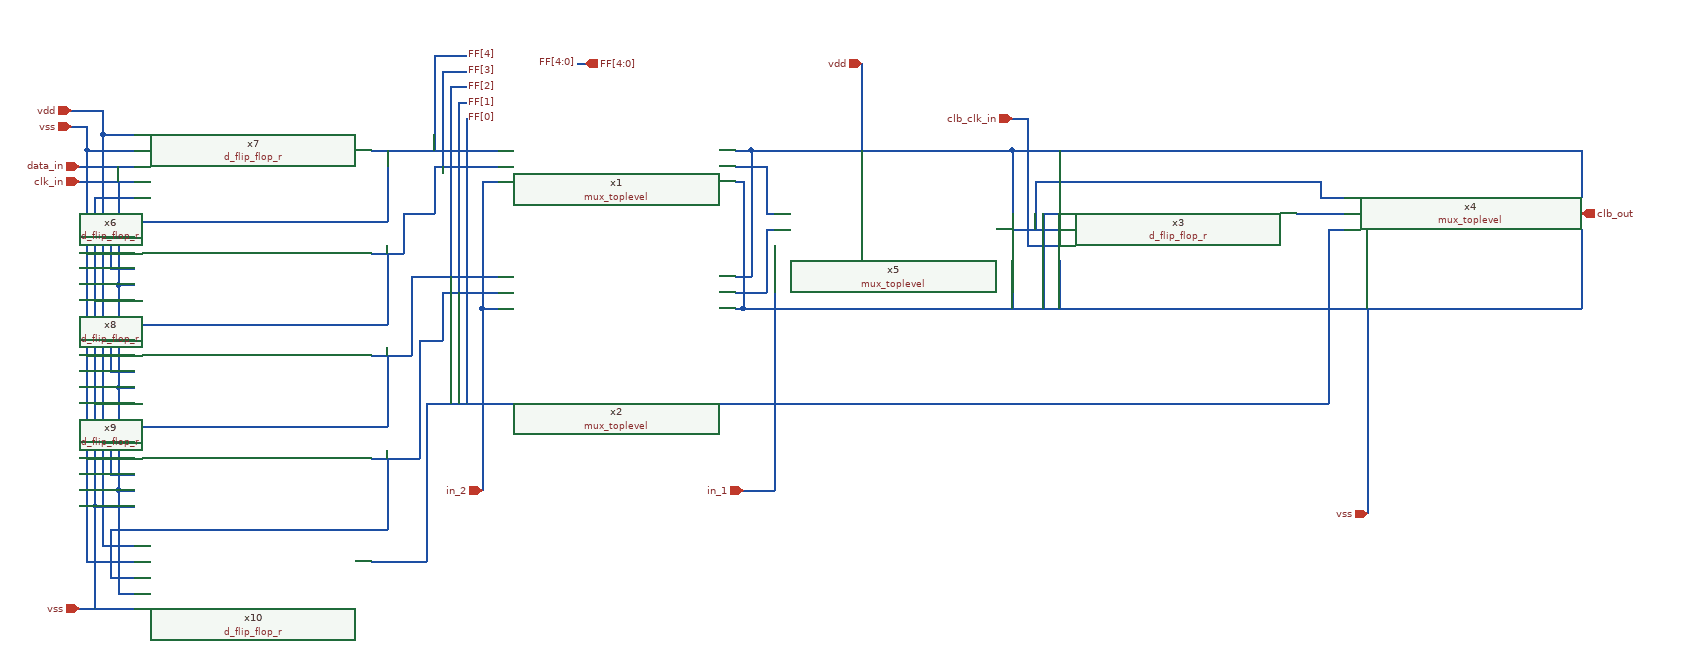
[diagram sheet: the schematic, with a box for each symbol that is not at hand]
v {xschem version=3.4.7 file_version=1.2}
G {}
K {}
V {}
S {}
E {}
N 230 -20 270 -20 {lab=#net1}
N 270 -20 270 40 {lab=#net1}
N 270 40 280 40 {lab=#net1}
N 230 140 270 140 {lab=#net2}
N 270 60 270 140 {lab=#net2}
N 270 60 280 60 {lab=#net2}
N 230 0 240 0 {lab=vss}
N 240 -0 240 160 {lab=vss}
N 230 160 240 160 {lab=vss}
N 230 120 250 120 {lab=vdd}
N 250 -40 250 120 {lab=vdd}
N 230 -40 250 -40 {lab=vdd}
N 250 -40 580 -40 {lab=vdd}
N 580 -40 580 40 {lab=vdd}
N 580 -40 1220 -40 {lab=vdd}
N 240 160 1220 160 {lab=vss}
N 580 80 580 160 {lab=vss}
N 580 60 640 60 {lab=#net3}
N 610 -0 610 60 {lab=#net3}
N 610 -0 900 -0 {lab=#net3}
N -90 -0 -90 160 {lab=in_2}
N -90 160 -70 160 {lab=in_2}
N -90 160 -90 270 {lab=in_2}
N 240 390 270 390 {lab=in_1}
N -90 -0 -70 0 {lab=in_2}
N -160 -40 -70 -40 {lab=FF[4]}
N -150 -20 -70 -20 {lab=FF[3]}
N -150 -20 -150 40 {lab=FF[3]}
N -160 40 -150 40 {lab=FF[3]}
N -160 120 -70 120 {lab=FF[2]}
N -160 200 -140 200 {lab=FF[1]}
N -140 140 -140 200 {lab=FF[1]}
N -140 140 -70 140 {lab=FF[1]}
N -90 270 -90 390 {lab=in_2}
N 270 390 280 390 {lab=in_1}
N -160 280 910 280 {lab=FF[0]}
N 910 280 920 280 {lab=FF[0]}
N 580 -80 590 -80 {lab=clb_clk_in}
N 1030 160 1030 420 {lab=vss}
N 390 -150 390 -40 {lab=vdd}
N 280 80 280 390 {lab=in_1}
N -110 -80 -110 280 {lab=FF[0]}
N -120 -100 -110 -100 {lab=FF[1]}
N -130 -120 -110 -120 {lab=FF[2]}
N -130 -120 -130 120 {lab=FF[2]}
N -120 -100 -120 140 {lab=FF[1]}
N -140 -140 -110 -140 {lab=FF[3]}
N -140 -140 -140 -20 {lab=FF[3]}
N -150 -160 -110 -160 {lab=FF[4]}
N -150 -160 -150 -40 {lab=FF[4]}
N 30 -150 40 -150 {lab=FF[4:0]}
N -230 -40 -160 -40 {lab=FF[4]}
N -190 40 -160 40 {lab=FF[3]}
N -190 40 -190 90 {lab=FF[3]}
N -230 90 -190 90 {lab=FF[3]}
N -230 220 -180 220 {lab=FF[2]}
N -180 120 -180 220 {lab=FF[2]}
N -180 120 -160 120 {lab=FF[2]}
N -170 200 -160 200 {lab=FF[1]}
N -170 200 -170 350 {lab=FF[1]}
N -230 350 -170 350 {lab=FF[1]}
N -160 280 -160 480 {lab=FF[0]}
N -230 480 -160 480 {lab=FF[0]}
N -600 -0 -530 -0 {lab=clk_in}
N -550 -0 -550 130 {lab=clk_in}
N -550 130 -530 130 {lab=clk_in}
N -550 130 -550 260 {lab=clk_in}
N -550 260 -530 260 {lab=clk_in}
N -550 260 -550 390 {lab=clk_in}
N -550 390 -530 390 {lab=clk_in}
N -550 390 -550 520 {lab=clk_in}
N -550 520 -530 520 {lab=clk_in}
N -600 -20 -530 -20 {lab=data_in}
N -210 -40 -210 40 {lab=FF[4]}
N -210 40 -210 50 {lab=FF[4]}
N -560 50 -210 50 {lab=FF[4]}
N -560 50 -560 110 {lab=FF[4]}
N -560 110 -530 110 {lab=FF[4]}
N -210 90 -210 180 {lab=FF[3]}
N -560 180 -210 180 {lab=FF[3]}
N -560 180 -560 240 {lab=FF[3]}
N -560 240 -530 240 {lab=FF[3]}
N -210 220 -210 310 {lab=FF[2]}
N -560 310 -210 310 {lab=FF[2]}
N -560 310 -560 370 {lab=FF[2]}
N -560 370 -530 370 {lab=FF[2]}
N -210 350 -210 430 {lab=FF[1]}
N -210 430 -210 440 {lab=FF[1]}
N -560 440 -210 440 {lab=FF[1]}
N -560 440 -560 500 {lab=FF[1]}
N -560 500 -530 500 {lab=FF[1]}
N -600 540 -530 540 {lab=vss}
N -580 410 -530 410 {lab=vss}
N -580 410 -580 540 {lab=vss}
N -580 20 -530 20 {lab=vss}
N -580 20 -580 410 {lab=vss}
N -580 280 -530 280 {lab=vss}
N -580 150 -530 150 {lab=vss}
N -610 -90 -570 -90 {lab=vdd}
N -570 -90 -570 -60 {lab=vdd}
N -570 -60 -530 -60 {lab=vdd}
N -570 -60 -570 460 {lab=vdd}
N -570 460 -530 460 {lab=vdd}
N -570 330 -530 330 {lab=vdd}
N -570 200 -530 200 {lab=vdd}
N -570 70 -530 70 {lab=vdd}
N -590 -40 -530 -40 {lab=vss}
N -590 -70 -590 -40 {lab=vss}
N -610 -70 -590 -70 {lab=vss}
N -590 -40 -590 480 {lab=vss}
N -590 480 -530 480 {lab=vss}
N -590 350 -530 350 {lab=vss}
N -590 220 -530 220 {lab=vss}
N -590 90 -530 90 {lab=vss}
N 940 40 1000 40 {lab=#net4}
N 900 -0 970 -0 {lab=#net3}
N 970 -0 970 20 {lab=#net3}
N 970 20 1000 20 {lab=#net3}
N 980 60 1000 60 {lab=FF[0]}
N 980 60 980 280 {lab=FF[0]}
N 920 280 980 280 {lab=FF[0]}
N 1300 -40 1300 20 {lab=vdd}
N 1220 -40 1300 -40 {lab=vdd}
N 1220 160 1300 160 {lab=vss}
N 1300 60 1300 160 {lab=vss}
N 640 -40 640 20 {lab=vdd}
N 620 40 640 40 {lab=vss}
N 620 40 620 160 {lab=vss}
N 590 -80 600 -80 {lab=clb_clk_in}
N 600 -80 600 80 {lab=clb_clk_in}
N 600 80 640 80 {lab=clb_clk_in}
N 640 100 640 160 {lab=vss}
C {ipin.sym} -600 -20 0 0 {name=p1 lab=data_in
}
C {ipin.sym} -600 0 0 0 {name=p2 lab=clk_in}
C {ipin.sym} 580 -80 0 0 {name=p5 lab=clb_clk_in}
C {iopin.sym} 1030 420 0 0 {name=p9 lab=vss}
C {iopin.sym} 390 -150 2 0 {name=p10 lab=vdd}
C {opin.sym} 1300 40 0 0 {name=p12 lab=clb_out}
C {ipin.sym} 240 390 0 0 {name=p13 lab=in_1}
C {ipin.sym} -90 390 0 0 {name=p14 lab=in_2}
C {sscs-chipathon2025-LNA/designs/libs/core_fpga/mux2x1_transmission_gate/mux_toplevel.sym} 80 20 0 0 {name=x1}
C {opin.sym} 40 -150 0 0 {name=p8 lab=FF[4:0]}
C {lab_wire.sym} -110 -160 2 0 {name=p11 sig_type=std_logic lab=FF[4]}
C {lab_wire.sym} -110 -140 2 0 {name=p3 sig_type=std_logic lab=FF[3]}
C {lab_wire.sym} -110 -120 2 0 {name=p4 sig_type=std_logic lab=FF[2]}
C {lab_wire.sym} -110 -100 2 0 {name=p6 sig_type=std_logic lab=FF[1]}
C {lab_wire.sym} -110 -80 2 0 {name=p7 sig_type=std_logic lab=FF[0]}
C {lab_wire.sym} 30 -150 0 0 {name=p15 sig_type=std_logic lab=FF[4:0]}
C {iopin.sym} -600 540 2 0 {name=p16 lab=vss}
C {iopin.sym} -610 -90 2 0 {name=p17 lab=vdd}
C {iopin.sym} -610 -70 2 0 {name=p18 lab=vss}
C {sscs-chipathon2025-LNA/designs/libs/core_fpga/d_flip_flop/d_flip_flop_r.sym} -380 110 0 0 {name=x6}
C {sscs-chipathon2025-LNA/designs/libs/core_fpga/d_flip_flop/d_flip_flop_r.sym} -380 -20 0 0 {name=x7}
C {sscs-chipathon2025-LNA/designs/libs/core_fpga/d_flip_flop/d_flip_flop_r.sym} -380 240 0 0 {name=x8}
C {sscs-chipathon2025-LNA/designs/libs/core_fpga/d_flip_flop/d_flip_flop_r.sym} -380 370 0 0 {name=x9}
C {sscs-chipathon2025-LNA/designs/libs/core_fpga/d_flip_flop/d_flip_flop_r.sym} -380 500 0 0 {name=x10}
C {sscs-chipathon2025-LNA/designs/libs/core_fpga/d_flip_flop/d_flip_flop_r.sym} 790 60 0 0 {name=x3}
C {sscs-chipathon2025-LNA/designs/libs/core_fpga/mux2x1_transmission_gate/mux_toplevel.sym} 80 180 0 0 {name=x2}
C {sscs-chipathon2025-LNA/designs/libs/core_fpga/mux2x1_transmission_gate/mux_toplevel.sym} 430 100 0 0 {name=x5}
C {sscs-chipathon2025-LNA/designs/libs/core_fpga/mux2x1_transmission_gate/mux_toplevel.sym} 1150 80 0 0 {name=x4}
